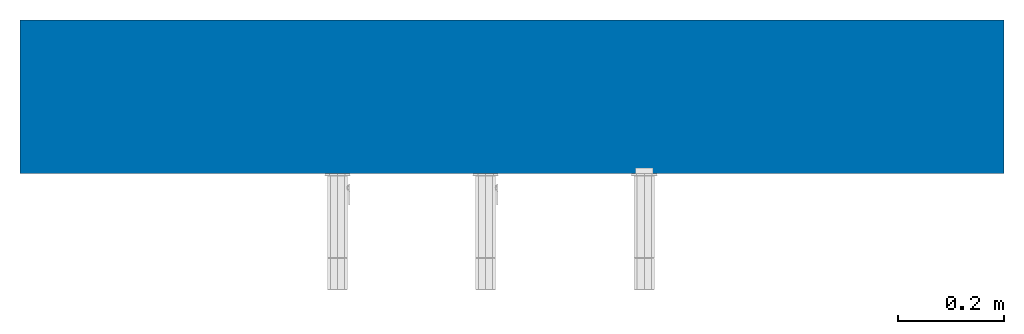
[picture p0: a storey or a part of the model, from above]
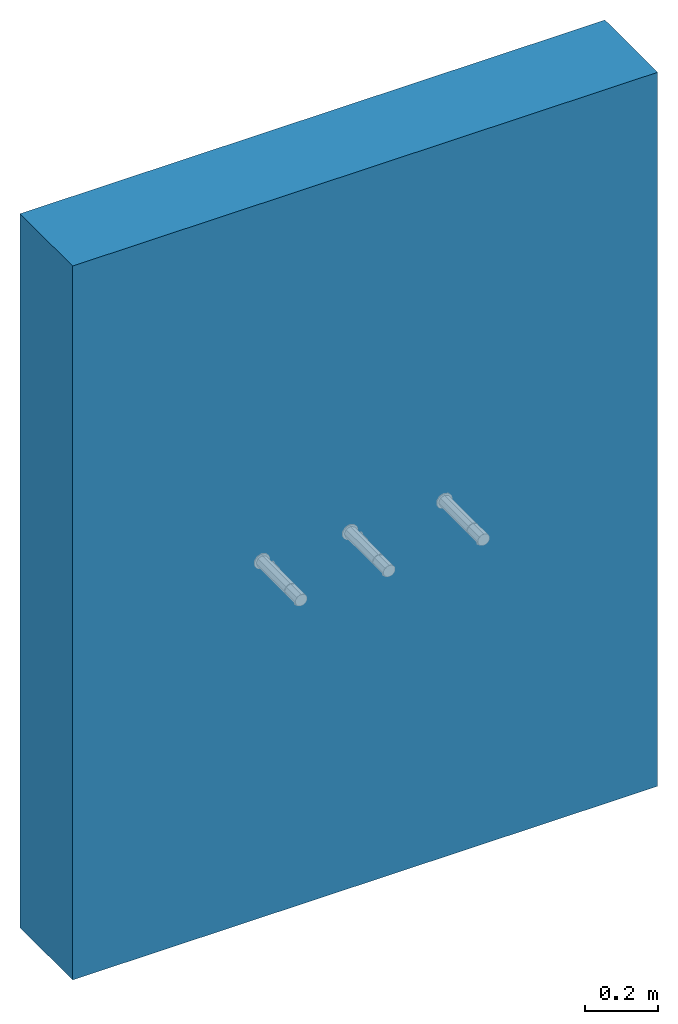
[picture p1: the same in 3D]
Properties of the parts of a building model (IFC2X3)

# File
Description: ViewDefinition [CoordinationView]
File name: Project Number
Time: 2018-10-12T06:47:01
Written by: The EXPRESS Data Manager Version 5.02.0100.07 : 28 Aug 2013
Made in: 20140606_1530(x64) - Exporter 2015.0.2014.0606 - Default UI
Comment: STEP Physical File produced by: The EXPRESS Data Manager Version 5.02.0100.07 : 28 Aug 2013 * Module: EDMstepFileFactory/EDMstandAlone * Creation date: Fri Oct 12 06:47:01 2018 * Host: SarahSams-HP * Database: C:\Users\SARAHS~1\AppData\Local\Temp\{47D517F5-AD69-4667-BC84-2E504B89526B}\ifc * Database version: 5507 * Database creation date: Fri Oct 12 06:47:00 2018 * Schema: IFC2X3 * Model: DataRepository.ifc * Model creation date: Fri Oct 12 06:47:00 2018 * Header model: DataRepository.ifc_HeaderModel * Header model creation date: Fri Oct 12 06:47:00 2018 * EDMuser: sdai-user * EDMgroup: sdai-group * License ID and type: 5605 : Permanent license. Expiry date: * EDMstepFileFactory options: 020000

# IfcProject, Project Number
LongName: Project Name; Phase: Project Status

# IfcSite, Default
RefLatitude: 51, 30, 0, 549316; RefLongitude: 0, -7, -34, -450321; RefElevation: 0 mm
Other - Category: Project Information; Client Name: Owner; Project Address: Enter address here; Project Issue Date: Issue Date; Project Name: Project Name; Project Number: Project Number; Project Status: Project Status

# IfcBuilding
Pset_BuildingCommon - NumberOfStoreys: 1
Other - Category: Project Information; Client Name: Owner; Project Address: Enter address here; Project Issue Date: Issue Date; Project Name: Project Name; Project Number: Project Number; Project Status: Project Status

# IfcBuildingStorey, Level 0
LongName: Level 0; Elevation: 0 mm
Other - Category: Levels; Family Name: Level; Family: Level: Circle Head - Project Datum; Family and Type: Level: Circle Head - Project Datum; Type: Level: Circle Head - Project Datum; Type Id: Level: Circle Head - Project Datum
Identity Data - Type Name: Circle Head - Project Datum; Structural: no; Building Story: yes; Name: Level 0
Graphics - Color: 0; Line Pattern: Centre; Line Weight: 1; Symbol: Anno_Level_Head_Circle: Standard; Symbol at End 1 Default: yes; Symbol at End 2 Default: no
Constraints - Elevation Base: Project Base Point; Elevation: 0 mm
Dimensions - Computation Height: 0 mm

# IfcFlowController: Battery Pack Brushed Stainless Steel, Duten_WtrSplyFitngsForWshBsnsAndTrghs_R381-MP:Battery Pack Brushed Stainless Steel:307634
In: Level 0
Type - PredefinedType: FAUCET; Classification: C1030210 Bath & Toilet Accessories - Commercial (Uniformat); Material: Duten_Metal_BrushedStainlessSteel, Duten_Plastic_Black
Type - Constraints - Default Elevation: 1200 mm
Type - General - Author: Diane Butterworth Ltd; ManufacturerName: Duten; ManufacturerURL: http://www.duten.fr/; NBSDescription: Taps and water supply fittings for wash basins and troughs; NBSReference: 45-35-70/371; ProductInformation: http://www.duten.fr/?page_id=37&ca=robinetterie-inox; Revision: n/a; Uniclass2015Code: Pr_40_20_87_98; Uniclass2015Title: Washbasin taps; Uniclass2015Version: Pr-Products v1.10
Type - Identity Data - Assembly Code: C1030210; Assembly Description: Bath & Toilet Accessories - Commercial; Cost: 0; Description: Brushed Stainless Steel; Keynote: Pr_40_20_87_98; Manufacturer: Duten; Model: R380-MP; Type Comments: Brushed Stainless Steel; Type Name: Battery Pack Brushed Stainless Steel; URL: http://www.duten.fr/
Type - Materials and Finishes - SensorFinish: Duten_Plastic_Black; TapFinish: Duten_Metal_BrushedStainlessSteel
Type - Other - Category: Plumbing Fixtures; AccessibilityPerformance: n/a; AssetIdentifier: n/a; AssetType: Moveable; BarCode: n/a; CodePerformance: WRAS Approved. ASME A112.18.1-2011/CSA B125.1-11; Color: Defined by Finish; Constituents: Stainless Steel Stem, Temperature Control, Concealed Battery Power.; DurationUnit: Years; ExpectedLife: 10; Family Name: Duten_WtrSplyFitngsForWshBsnsAndTrghs_R381-MP; Features: Temperature control faucet for wall mounted installations. For cold or premixed water. For concealed installations in brick walls. Powered by external IP67 battery box with 6x1.5 V AA; Finish: Available in Brushed, Polished or Matte Black Stainless Steel.; Grade: n/a; InstallationDate: 1900-12-31T23:59:59; Material: Stainless Steel; ModelNumber: R381-MP-S; ModelReference: Brushed Stainless Steel; Name: WaterSupplyFittingsForWashBasinsAndTroughs_R381-MP_Duten; ReplacementCost: 0; SerialNumber: n/a; Shape: Cylindrical; Size: (H) 1730mm x (L) 222mm x (W) 50mm; SustainabilityPerformance: n/a; TagNumber: n/a; WarrantyDescription: n/a; WarrantyDurationLabor: contact@duten.fr; WarrantyDurationParts: contact@duten.fr; WarrantyDurationUnit: Years; WarrantyGuarantorLabor: 10; WarrantyGuarantorParts: 10; WarrantyStartDate: 1900-12-31T23:59:59
Type - Plumbing - CW Connection: yes; FlowRate: 3L/min; HW Connection: yes; Vent Connection: no; Waste Connection: no; WaterSupplyTemperatureMaximum: 70 °C
Pset_ManufacturerTypeInformation - ModelReference: Brushed Stainless Steel; Manufacturer: Duten
Pset_DistributionFlowElementCommon - Reference: n/a
Constraints - Elevation: 1200 mm; Host: Basic Wall : Wall-Ext_102Bwk-75Ins-100LBlk-12P; Level: Level: Level 0
Dimensions - Area: 0.0178054 m2; Volume: 0.000260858 m3
Identity Data - Mark: 13
Mechanical - System Classification: Other,Controls,Other,Controls,Other,Hydronic Supply
Other - Family: Duten_WtrSplyFitngsForWshBsnsAndTrghs_R381-MP: Battery Pack Brushed Stainless Steel; Family and Type: Duten_WtrSplyFitngsForWshBsnsAndTrghs_R381-MP: Battery Pack Brushed Stainless Steel; Schedule Level: Level: Level 0; Type: Duten_WtrSplyFitngsForWshBsnsAndTrghs_R381-MP: Battery Pack Brushed Stainless Steel; Type Id: Duten_WtrSplyFitngsForWshBsnsAndTrghs_R381-MP: Battery Pack Brushed Stainless Steel
Phasing - Phase Created: New Construction

# IfcFlowController: Battery Pack Matte Black, Duten_WtrSplyFitngsForWshBsnsAndTrghs_R381-MP:Battery Pack Matte Black:307675
In: Level 0
Type - PredefinedType: FAUCET; Classification: C1030210 Bath & Toilet Accessories - Commercial (Uniformat); Material: Duten_Metal_MatteBlack, Duten_Plastic_Black
Type - Constraints - Default Elevation: 1200 mm
Type - General - Author: Diane Butterworth Ltd; ManufacturerName: Duten; ManufacturerURL: http://www.duten.fr/; NBSDescription: Taps and water supply fittings for wash basins and troughs; NBSReference: 45-35-70/371; ProductInformation: http://www.duten.fr/?page_id=37&ca=robinetterie-inox; Revision: n/a; Uniclass2015Code: Pr_40_20_87_98; Uniclass2015Title: Washbasin taps; Uniclass2015Version: Pr-Products v1.10
Type - Identity Data - Assembly Code: C1030210; Assembly Description: Bath & Toilet Accessories - Commercial; Cost: 0; Description: Matte Black; Keynote: Pr_40_20_87_98; Manufacturer: Duten; Model: R380-MP; Type Comments: Matte Black; Type Name: Battery Pack Matte Black; URL: http://www.duten.fr/
Type - Materials and Finishes - SensorFinish: Duten_Plastic_Black; TapFinish: Duten_Metal_MatteBlack
Type - Other - Category: Plumbing Fixtures; AccessibilityPerformance: n/a; AssetIdentifier: n/a; AssetType: Moveable; BarCode: n/a; CodePerformance: WRAS Approved. ASME A112.18.1-2011/CSA B125.1-11; Color: Defined by Finish; Constituents: Stainless Steel Stem, Temperature Control, Concealed Battery Power.; DurationUnit: Years; ExpectedLife: 10; Family Name: Duten_WtrSplyFitngsForWshBsnsAndTrghs_R381-MP; Features: Temperature control faucet for wall mounted installations. For cold or premixed water. For concealed installations in brick walls. Powered by external IP67 battery box with 6x1.5 V AA; Finish: Available in Brushed, Polished or Matte Black Stainless Steel.; Grade: n/a; InstallationDate: 1900-12-31T23:59:59; Material: Stainless Steel; ModelNumber: R381-MP-N; ModelReference: Matte Black; Name: WaterSupplyFittingsForWashBasinsAndTroughs_R381-MP_Duten; ReplacementCost: 0; SerialNumber: n/a; Shape: Cylindrical; Size: (H) 1730mm x (L) 222mm x (W) 50mm; SustainabilityPerformance: n/a; TagNumber: n/a; WarrantyDescription: n/a; WarrantyDurationLabor: contact@duten.fr; WarrantyDurationParts: contact@duten.fr; WarrantyDurationUnit: Years; WarrantyGuarantorLabor: 10; WarrantyGuarantorParts: 10; WarrantyStartDate: 1900-12-31T23:59:59
Type - Plumbing - CW Connection: yes; HW Connection: yes; Vent Connection: no; Waste Connection: no; FlowRate: 3L/min; WaterSupplyTemperatureMaximum: 70 °C
Pset_ManufacturerTypeInformation - ModelReference: Matte Black; Manufacturer: Duten
Pset_DistributionFlowElementCommon - Reference: n/a
Constraints - Level: Level: Level 0; Elevation: 1200 mm; Host: Basic Wall : Wall-Ext_102Bwk-75Ins-100LBlk-12P
Dimensions - Area: 0.0178054 m2; Volume: 0.000260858 m3
Identity Data - Mark: 14
Mechanical - System Classification: Other,Controls,Other,Controls,Other,Hydronic Supply
Other - Schedule Level: Level: Level 0; Family: Duten_WtrSplyFitngsForWshBsnsAndTrghs_R381-MP: Battery Pack Matte Black; Family and Type: Duten_WtrSplyFitngsForWshBsnsAndTrghs_R381-MP: Battery Pack Matte Black; Type: Duten_WtrSplyFitngsForWshBsnsAndTrghs_R381-MP: Battery Pack Matte Black; Type Id: Duten_WtrSplyFitngsForWshBsnsAndTrghs_R381-MP: Battery Pack Matte Black
Phasing - Phase Created: New Construction

# IfcFlowController: Battery Pack Polished Stainless Steel, Duten_WtrSplyFitngsForWshBsnsAndTrghs_R380-MP:Battery Pack Polished Stainless Steel:307698
In: Level 0
Type - PredefinedType: FAUCET; Classification: C1030210 Bath & Toilet Accessories - Commercial (Uniformat); Material: Duten_Plastic_Black, Duten_Metal_Polished
Type - Constraints - Default Elevation: 1200 mm
Type - General - Author: Diane Butterworth Ltd; ManufacturerName: Duten; ManufacturerURL: http://www.duten.fr/; NBSDescription: Taps and water supply fittings for wash basins and troughs; NBSReference: 45-35-70/371; ProductInformation: http://www.duten.fr/?post_type=produits&p=1105&ca=robinetterie-inox; Revision: n/a; Uniclass2015Code: Pr_40_20_87_98; Uniclass2015Title: Washbasin taps; Uniclass2015Version: Pr-Products v1.10
Type - Identity Data - Assembly Code: C1030210; Assembly Description: Bath & Toilet Accessories - Commercial; Cost: 0; Description: Battery Pack Polished Stainless Steel; Keynote: Pr_40_20_87_98; Manufacturer: Duten; Model: R380-MP; Type Comments: Battery Pack Polished Stainless Steel; Type Name: Battery Pack Polished Stainless Steel; URL: http://www.duten.fr/
Type - Materials and Finishes - SensorFinish: Duten_Plastic_Black; TapFinish: Duten_Metal_Polished
Type - Other - AccessibilityPerformance: n/a; AssetIdentifier: n/a; AssetType: Moveable; BarCode: n/a; Category: Pr_40_20_87_98: Washbasin taps; CodePerformance: WRAS Approved. ASME A112.18.1-2011/CSA B125.1-11; Color: Defined by Finish; Constituents: Stainless Steel Stem, Touchless Sensor, Concealed Battery Power.; DurationUnit: Years; ExpectedLife: 10; Family Name: Duten_WtrSplyFitngsForWshBsnsAndTrghs_R380-MP; Features: Touch free electronic faucet for wall mounted installations. For cold or premixed water. For concealed installations in brick walls. Self adjusting infrared sensor. Powered by external IP67 battery box with 6x1.5 V AA Alkaline batteries. Filters included.; Finish: Available in Brushed, Polished or Matte Black Stainless Steel.; Grade: n/a; InstallationDate: 1900-12-31T23:59:59; Material: Stainless Steel; ModelNumber: R380-MP-B; ModelReference: Battery Pack Polished Stainless Steel; Name: WaterSupplyFittingsForWashBasinsAndTroughs_R380-MP_Duten; ReplacementCost: 0; SerialNumber: n/a; Shape: Cylindrical; Size: (H) 1730mm x (L) 220mm x (W) 50mm; SustainabilityPerformance: n/a; TagNumber: n/a; WarrantyDescription: n/a; WarrantyDurationLabor: contact@duten.fr; WarrantyDurationParts: contact@duten.fr; WarrantyDurationUnit: Years; WarrantyGuarantorLabor: 10; WarrantyGuarantorParts: 10; WarrantyStartDate: 1900-12-31T23:59:59
Type - Plumbing - CW Connection: yes; HW Connection: yes; Vent Connection: no; Waste Connection: no; FlowRate: 3L/min; WaterSupplyTemperatureMaximum: 70 °C
Pset_ManufacturerTypeInformation - ModelReference: Battery Pack Polished Stainless Steel; Manufacturer: Duten
Pset_DistributionFlowElementCommon - Reference: n/a
Constraints - Level: Level: Level 0; Elevation: 1200 mm; Host: Basic Wall : Wall-Ext_102Bwk-75Ins-100LBlk-12P
Dimensions - Area: 0.0169233 m2; Volume: 0.000261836 m3
Identity Data - Mark: 15
Mechanical - System Classification: Other,Controls
Other - Category: Plumbing Fixtures; Schedule Level: Level: Level 0; Family: Duten_WtrSplyFitngsForWshBsnsAndTrghs_R380-MP: Battery Pack Polished Stainless Steel; Family and Type: Duten_WtrSplyFitngsForWshBsnsAndTrghs_R380-MP: Battery Pack Polished Stainless Steel; Type: Duten_WtrSplyFitngsForWshBsnsAndTrghs_R380-MP: Battery Pack Polished Stainless Steel; Type Id: Duten_WtrSplyFitngsForWshBsnsAndTrghs_R380-MP: Battery Pack Polished Stainless Steel
Phasing - Phase Created: New Construction

# IfcWallStandardCase: Basic Wall:Wall-Ext_102Bwk-75Ins-100LBlk-12P, Basic Wall:Wall-Ext_102Bwk-75Ins-100LBlk-12P:259702
In: Level 0
Type - PredefinedType: STANDARD; Material: Brick, Common 102.5 mm, Fiberglass Batt 75 mm, Concrete Masonry Units _Low Density 100 mm, Plaster 12.5 mm
Type - Analytical Properties - Absorptance: 0.7; Heat Transfer Coefficient (U): 0.235926; Roughness: 3; Thermal mass: 300303; Thermal Resistance (R): 4.23862
Type - Construction - Function: Exterior; Width: 290 mm; Wrapping at Inserts: Both
Type - Graphics - Coarse Scale Fill Color: 12632256; Coarse Scale Fill Pattern: Solid fill
Type - Identity Data - Keynote: F10; Type Name: Wall-Ext_102Bwk-75Ins-100LBlk-12P
Type - Materials and Finishes - Structural Material: Concrete Masonry Units _Low Density
Type - Other - Category: Walls; Family Name: Basic Wall
Constraints - Base Constraint: Level: Level 0; Base Extension Distance: 0 mm; Base is Attached: no; Base Offset: 0 mm; Location Line: Wall Centerline; Related to Mass: no; Room Bounding: yes; Top Extension Distance: 0 mm; Top is Attached: no; Top Offset: 0 mm; Unconnected Height: 2400 mm
Dimensions - Area: 4.464 m2; Length: 1860 mm; Volume: 1.29456 m3
Other - Family: Basic Wall: Wall-Ext_102Bwk-75Ins-100LBlk-12P; Family and Type: Basic Wall: Wall-Ext_102Bwk-75Ins-100LBlk-12P; Type: Basic Wall: Wall-Ext_102Bwk-75Ins-100LBlk-12P; Type Id: Basic Wall: Wall-Ext_102Bwk-75Ins-100LBlk-12P
Phasing - Phase Created: New Construction
Structural - Enable Analytical Model: no; Structural: no; Structural Usage: Non-bearing
Pset_WallCommon - Reference: Wall-Ext_102Bwk-75Ins-100LBlk-12P; LoadBearing: no; ExtendToStructure: no; IsExternal: yes; ThermalTransmittance: 0.235926 kg/K/s3
